VERSION 5.7 ;
BUSBITCHARS "[]" ;
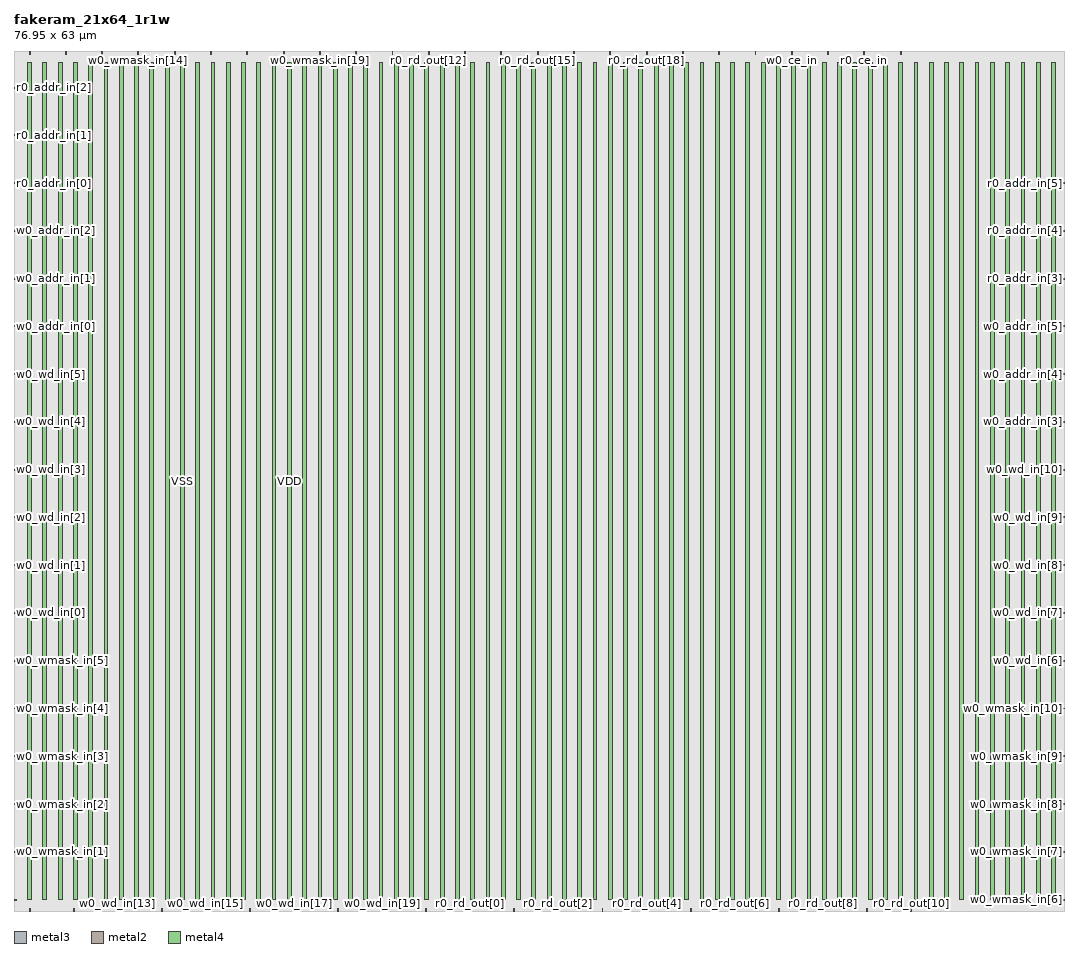
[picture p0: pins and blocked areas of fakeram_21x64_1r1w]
MACRO fakeram_21x64_1r1w
  FOREIGN fakeram_21x64_1r1w 0 0 ;
  SYMMETRY X Y R90 ;
  SIZE 76.950 BY 63.000 ;
  CLASS BLOCK ;
  PIN w0_wmask_in[0]
    DIRECTION INPUT ;
    USE SIGNAL ;
    SHAPE ABUTMENT ;
    PORT
      LAYER metal3 ;
      RECT 0.000 0.805 0.210 0.875 ;
    END
  END w0_wmask_in[0]
  PIN w0_wmask_in[1]
    DIRECTION INPUT ;
    USE SIGNAL ;
    SHAPE ABUTMENT ;
    PORT
      LAYER metal3 ;
      RECT 0.000 4.305 0.210 4.375 ;
    END
  END w0_wmask_in[1]
  PIN w0_wmask_in[2]
    DIRECTION INPUT ;
    USE SIGNAL ;
    SHAPE ABUTMENT ;
    PORT
      LAYER metal3 ;
      RECT 0.000 7.805 0.210 7.875 ;
    END
  END w0_wmask_in[2]
  PIN w0_wmask_in[3]
    DIRECTION INPUT ;
    USE SIGNAL ;
    SHAPE ABUTMENT ;
    PORT
      LAYER metal3 ;
      RECT 0.000 11.305 0.210 11.375 ;
    END
  END w0_wmask_in[3]
  PIN w0_wmask_in[4]
    DIRECTION INPUT ;
    USE SIGNAL ;
    SHAPE ABUTMENT ;
    PORT
      LAYER metal3 ;
      RECT 0.000 14.805 0.210 14.875 ;
    END
  END w0_wmask_in[4]
  PIN w0_wmask_in[5]
    DIRECTION INPUT ;
    USE SIGNAL ;
    SHAPE ABUTMENT ;
    PORT
      LAYER metal3 ;
      RECT 0.000 18.305 0.210 18.375 ;
    END
  END w0_wmask_in[5]
  PIN w0_wmask_in[6]
    DIRECTION INPUT ;
    USE SIGNAL ;
    SHAPE ABUTMENT ;
    PORT
      LAYER metal3 ;
      RECT 76.740 0.805 76.950 0.875 ;
    END
  END w0_wmask_in[6]
  PIN w0_wmask_in[7]
    DIRECTION INPUT ;
    USE SIGNAL ;
    SHAPE ABUTMENT ;
    PORT
      LAYER metal3 ;
      RECT 76.740 4.305 76.950 4.375 ;
    END
  END w0_wmask_in[7]
  PIN w0_wmask_in[8]
    DIRECTION INPUT ;
    USE SIGNAL ;
    SHAPE ABUTMENT ;
    PORT
      LAYER metal3 ;
      RECT 76.740 7.805 76.950 7.875 ;
    END
  END w0_wmask_in[8]
  PIN w0_wmask_in[9]
    DIRECTION INPUT ;
    USE SIGNAL ;
    SHAPE ABUTMENT ;
    PORT
      LAYER metal3 ;
      RECT 76.740 11.305 76.950 11.375 ;
    END
  END w0_wmask_in[9]
  PIN w0_wmask_in[10]
    DIRECTION INPUT ;
    USE SIGNAL ;
    SHAPE ABUTMENT ;
    PORT
      LAYER metal3 ;
      RECT 76.740 14.805 76.950 14.875 ;
    END
  END w0_wmask_in[10]
  PIN w0_wmask_in[11]
    DIRECTION INPUT ;
    USE SIGNAL ;
    SHAPE ABUTMENT ;
    PORT
      LAYER metal2 ;
      RECT 1.105 62.790 1.175 63.000 ;
    END
  END w0_wmask_in[11]
  PIN w0_wmask_in[12]
    DIRECTION INPUT ;
    USE SIGNAL ;
    SHAPE ABUTMENT ;
    PORT
      LAYER metal2 ;
      RECT 3.765 62.790 3.835 63.000 ;
    END
  END w0_wmask_in[12]
  PIN w0_wmask_in[13]
    DIRECTION INPUT ;
    USE SIGNAL ;
    SHAPE ABUTMENT ;
    PORT
      LAYER metal2 ;
      RECT 6.425 62.790 6.495 63.000 ;
    END
  END w0_wmask_in[13]
  PIN w0_wmask_in[14]
    DIRECTION INPUT ;
    USE SIGNAL ;
    SHAPE ABUTMENT ;
    PORT
      LAYER metal2 ;
      RECT 9.085 62.790 9.155 63.000 ;
    END
  END w0_wmask_in[14]
  PIN w0_wmask_in[15]
    DIRECTION INPUT ;
    USE SIGNAL ;
    SHAPE ABUTMENT ;
    PORT
      LAYER metal2 ;
      RECT 11.745 62.790 11.815 63.000 ;
    END
  END w0_wmask_in[15]
  PIN w0_wmask_in[16]
    DIRECTION INPUT ;
    USE SIGNAL ;
    SHAPE ABUTMENT ;
    PORT
      LAYER metal2 ;
      RECT 14.405 62.790 14.475 63.000 ;
    END
  END w0_wmask_in[16]
  PIN w0_wmask_in[17]
    DIRECTION INPUT ;
    USE SIGNAL ;
    SHAPE ABUTMENT ;
    PORT
      LAYER metal2 ;
      RECT 17.065 62.790 17.135 63.000 ;
    END
  END w0_wmask_in[17]
  PIN w0_wmask_in[18]
    DIRECTION INPUT ;
    USE SIGNAL ;
    SHAPE ABUTMENT ;
    PORT
      LAYER metal2 ;
      RECT 19.725 62.790 19.795 63.000 ;
    END
  END w0_wmask_in[18]
  PIN w0_wmask_in[19]
    DIRECTION INPUT ;
    USE SIGNAL ;
    SHAPE ABUTMENT ;
    PORT
      LAYER metal2 ;
      RECT 22.385 62.790 22.455 63.000 ;
    END
  END w0_wmask_in[19]
  PIN w0_wmask_in[20]
    DIRECTION INPUT ;
    USE SIGNAL ;
    SHAPE ABUTMENT ;
    PORT
      LAYER metal2 ;
      RECT 25.045 62.790 25.115 63.000 ;
    END
  END w0_wmask_in[20]
  PIN w0_wd_in[0]
    DIRECTION INPUT ;
    USE SIGNAL ;
    SHAPE ABUTMENT ;
    PORT
      LAYER metal3 ;
      RECT 0.000 21.805 0.210 21.875 ;
    END
  END w0_wd_in[0]
  PIN w0_wd_in[1]
    DIRECTION INPUT ;
    USE SIGNAL ;
    SHAPE ABUTMENT ;
    PORT
      LAYER metal3 ;
      RECT 0.000 25.305 0.210 25.375 ;
    END
  END w0_wd_in[1]
  PIN w0_wd_in[2]
    DIRECTION INPUT ;
    USE SIGNAL ;
    SHAPE ABUTMENT ;
    PORT
      LAYER metal3 ;
      RECT 0.000 28.805 0.210 28.875 ;
    END
  END w0_wd_in[2]
  PIN w0_wd_in[3]
    DIRECTION INPUT ;
    USE SIGNAL ;
    SHAPE ABUTMENT ;
    PORT
      LAYER metal3 ;
      RECT 0.000 32.305 0.210 32.375 ;
    END
  END w0_wd_in[3]
  PIN w0_wd_in[4]
    DIRECTION INPUT ;
    USE SIGNAL ;
    SHAPE ABUTMENT ;
    PORT
      LAYER metal3 ;
      RECT 0.000 35.805 0.210 35.875 ;
    END
  END w0_wd_in[4]
  PIN w0_wd_in[5]
    DIRECTION INPUT ;
    USE SIGNAL ;
    SHAPE ABUTMENT ;
    PORT
      LAYER metal3 ;
      RECT 0.000 39.305 0.210 39.375 ;
    END
  END w0_wd_in[5]
  PIN w0_wd_in[6]
    DIRECTION INPUT ;
    USE SIGNAL ;
    SHAPE ABUTMENT ;
    PORT
      LAYER metal3 ;
      RECT 76.740 18.305 76.950 18.375 ;
    END
  END w0_wd_in[6]
  PIN w0_wd_in[7]
    DIRECTION INPUT ;
    USE SIGNAL ;
    SHAPE ABUTMENT ;
    PORT
      LAYER metal3 ;
      RECT 76.740 21.805 76.950 21.875 ;
    END
  END w0_wd_in[7]
  PIN w0_wd_in[8]
    DIRECTION INPUT ;
    USE SIGNAL ;
    SHAPE ABUTMENT ;
    PORT
      LAYER metal3 ;
      RECT 76.740 25.305 76.950 25.375 ;
    END
  END w0_wd_in[8]
  PIN w0_wd_in[9]
    DIRECTION INPUT ;
    USE SIGNAL ;
    SHAPE ABUTMENT ;
    PORT
      LAYER metal3 ;
      RECT 76.740 28.805 76.950 28.875 ;
    END
  END w0_wd_in[9]
  PIN w0_wd_in[10]
    DIRECTION INPUT ;
    USE SIGNAL ;
    SHAPE ABUTMENT ;
    PORT
      LAYER metal3 ;
      RECT 76.740 32.305 76.950 32.375 ;
    END
  END w0_wd_in[10]
  PIN w0_wd_in[11]
    DIRECTION INPUT ;
    USE SIGNAL ;
    SHAPE ABUTMENT ;
    PORT
      LAYER metal2 ;
      RECT 1.105 0.000 1.175 0.210 ;
    END
  END w0_wd_in[11]
  PIN w0_wd_in[12]
    DIRECTION INPUT ;
    USE SIGNAL ;
    SHAPE ABUTMENT ;
    PORT
      LAYER metal2 ;
      RECT 4.335 0.000 4.405 0.210 ;
    END
  END w0_wd_in[12]
  PIN w0_wd_in[13]
    DIRECTION INPUT ;
    USE SIGNAL ;
    SHAPE ABUTMENT ;
    PORT
      LAYER metal2 ;
      RECT 7.565 0.000 7.635 0.210 ;
    END
  END w0_wd_in[13]
  PIN w0_wd_in[14]
    DIRECTION INPUT ;
    USE SIGNAL ;
    SHAPE ABUTMENT ;
    PORT
      LAYER metal2 ;
      RECT 10.795 0.000 10.865 0.210 ;
    END
  END w0_wd_in[14]
  PIN w0_wd_in[15]
    DIRECTION INPUT ;
    USE SIGNAL ;
    SHAPE ABUTMENT ;
    PORT
      LAYER metal2 ;
      RECT 14.025 0.000 14.095 0.210 ;
    END
  END w0_wd_in[15]
  PIN w0_wd_in[16]
    DIRECTION INPUT ;
    USE SIGNAL ;
    SHAPE ABUTMENT ;
    PORT
      LAYER metal2 ;
      RECT 17.255 0.000 17.325 0.210 ;
    END
  END w0_wd_in[16]
  PIN w0_wd_in[17]
    DIRECTION INPUT ;
    USE SIGNAL ;
    SHAPE ABUTMENT ;
    PORT
      LAYER metal2 ;
      RECT 20.485 0.000 20.555 0.210 ;
    END
  END w0_wd_in[17]
  PIN w0_wd_in[18]
    DIRECTION INPUT ;
    USE SIGNAL ;
    SHAPE ABUTMENT ;
    PORT
      LAYER metal2 ;
      RECT 23.715 0.000 23.785 0.210 ;
    END
  END w0_wd_in[18]
  PIN w0_wd_in[19]
    DIRECTION INPUT ;
    USE SIGNAL ;
    SHAPE ABUTMENT ;
    PORT
      LAYER metal2 ;
      RECT 26.945 0.000 27.015 0.210 ;
    END
  END w0_wd_in[19]
  PIN w0_wd_in[20]
    DIRECTION INPUT ;
    USE SIGNAL ;
    SHAPE ABUTMENT ;
    PORT
      LAYER metal2 ;
      RECT 30.175 0.000 30.245 0.210 ;
    END
  END w0_wd_in[20]
  PIN r0_rd_out[0]
    DIRECTION OUTPUT ;
    USE SIGNAL ;
    SHAPE ABUTMENT ;
    PORT
      LAYER metal2 ;
      RECT 33.405 0.000 33.475 0.210 ;
    END
  END r0_rd_out[0]
  PIN r0_rd_out[1]
    DIRECTION OUTPUT ;
    USE SIGNAL ;
    SHAPE ABUTMENT ;
    PORT
      LAYER metal2 ;
      RECT 36.635 0.000 36.705 0.210 ;
    END
  END r0_rd_out[1]
  PIN r0_rd_out[2]
    DIRECTION OUTPUT ;
    USE SIGNAL ;
    SHAPE ABUTMENT ;
    PORT
      LAYER metal2 ;
      RECT 39.865 0.000 39.935 0.210 ;
    END
  END r0_rd_out[2]
  PIN r0_rd_out[3]
    DIRECTION OUTPUT ;
    USE SIGNAL ;
    SHAPE ABUTMENT ;
    PORT
      LAYER metal2 ;
      RECT 43.095 0.000 43.165 0.210 ;
    END
  END r0_rd_out[3]
  PIN r0_rd_out[4]
    DIRECTION OUTPUT ;
    USE SIGNAL ;
    SHAPE ABUTMENT ;
    PORT
      LAYER metal2 ;
      RECT 46.325 0.000 46.395 0.210 ;
    END
  END r0_rd_out[4]
  PIN r0_rd_out[5]
    DIRECTION OUTPUT ;
    USE SIGNAL ;
    SHAPE ABUTMENT ;
    PORT
      LAYER metal2 ;
      RECT 49.555 0.000 49.625 0.210 ;
    END
  END r0_rd_out[5]
  PIN r0_rd_out[6]
    DIRECTION OUTPUT ;
    USE SIGNAL ;
    SHAPE ABUTMENT ;
    PORT
      LAYER metal2 ;
      RECT 52.785 0.000 52.855 0.210 ;
    END
  END r0_rd_out[6]
  PIN r0_rd_out[7]
    DIRECTION OUTPUT ;
    USE SIGNAL ;
    SHAPE ABUTMENT ;
    PORT
      LAYER metal2 ;
      RECT 56.015 0.000 56.085 0.210 ;
    END
  END r0_rd_out[7]
  PIN r0_rd_out[8]
    DIRECTION OUTPUT ;
    USE SIGNAL ;
    SHAPE ABUTMENT ;
    PORT
      LAYER metal2 ;
      RECT 59.245 0.000 59.315 0.210 ;
    END
  END r0_rd_out[8]
  PIN r0_rd_out[9]
    DIRECTION OUTPUT ;
    USE SIGNAL ;
    SHAPE ABUTMENT ;
    PORT
      LAYER metal2 ;
      RECT 62.475 0.000 62.545 0.210 ;
    END
  END r0_rd_out[9]
  PIN r0_rd_out[10]
    DIRECTION OUTPUT ;
    USE SIGNAL ;
    SHAPE ABUTMENT ;
    PORT
      LAYER metal2 ;
      RECT 65.705 0.000 65.775 0.210 ;
    END
  END r0_rd_out[10]
  PIN r0_rd_out[11]
    DIRECTION OUTPUT ;
    USE SIGNAL ;
    SHAPE ABUTMENT ;
    PORT
      LAYER metal2 ;
      RECT 27.705 62.790 27.775 63.000 ;
    END
  END r0_rd_out[11]
  PIN r0_rd_out[12]
    DIRECTION OUTPUT ;
    USE SIGNAL ;
    SHAPE ABUTMENT ;
    PORT
      LAYER metal2 ;
      RECT 30.365 62.790 30.435 63.000 ;
    END
  END r0_rd_out[12]
  PIN r0_rd_out[13]
    DIRECTION OUTPUT ;
    USE SIGNAL ;
    SHAPE ABUTMENT ;
    PORT
      LAYER metal2 ;
      RECT 33.025 62.790 33.095 63.000 ;
    END
  END r0_rd_out[13]
  PIN r0_rd_out[14]
    DIRECTION OUTPUT ;
    USE SIGNAL ;
    SHAPE ABUTMENT ;
    PORT
      LAYER metal2 ;
      RECT 35.685 62.790 35.755 63.000 ;
    END
  END r0_rd_out[14]
  PIN r0_rd_out[15]
    DIRECTION OUTPUT ;
    USE SIGNAL ;
    SHAPE ABUTMENT ;
    PORT
      LAYER metal2 ;
      RECT 38.345 62.790 38.415 63.000 ;
    END
  END r0_rd_out[15]
  PIN r0_rd_out[16]
    DIRECTION OUTPUT ;
    USE SIGNAL ;
    SHAPE ABUTMENT ;
    PORT
      LAYER metal2 ;
      RECT 41.005 62.790 41.075 63.000 ;
    END
  END r0_rd_out[16]
  PIN r0_rd_out[17]
    DIRECTION OUTPUT ;
    USE SIGNAL ;
    SHAPE ABUTMENT ;
    PORT
      LAYER metal2 ;
      RECT 43.665 62.790 43.735 63.000 ;
    END
  END r0_rd_out[17]
  PIN r0_rd_out[18]
    DIRECTION OUTPUT ;
    USE SIGNAL ;
    SHAPE ABUTMENT ;
    PORT
      LAYER metal2 ;
      RECT 46.325 62.790 46.395 63.000 ;
    END
  END r0_rd_out[18]
  PIN r0_rd_out[19]
    DIRECTION OUTPUT ;
    USE SIGNAL ;
    SHAPE ABUTMENT ;
    PORT
      LAYER metal2 ;
      RECT 48.985 62.790 49.055 63.000 ;
    END
  END r0_rd_out[19]
  PIN r0_rd_out[20]
    DIRECTION OUTPUT ;
    USE SIGNAL ;
    SHAPE ABUTMENT ;
    PORT
      LAYER metal2 ;
      RECT 51.645 62.790 51.715 63.000 ;
    END
  END r0_rd_out[20]
  PIN w0_addr_in[0]
    DIRECTION INPUT ;
    USE SIGNAL ;
    SHAPE ABUTMENT ;
    PORT
      LAYER metal3 ;
      RECT 0.000 42.805 0.210 42.875 ;
    END
  END w0_addr_in[0]
  PIN w0_addr_in[1]
    DIRECTION INPUT ;
    USE SIGNAL ;
    SHAPE ABUTMENT ;
    PORT
      LAYER metal3 ;
      RECT 0.000 46.305 0.210 46.375 ;
    END
  END w0_addr_in[1]
  PIN w0_addr_in[2]
    DIRECTION INPUT ;
    USE SIGNAL ;
    SHAPE ABUTMENT ;
    PORT
      LAYER metal3 ;
      RECT 0.000 49.805 0.210 49.875 ;
    END
  END w0_addr_in[2]
  PIN w0_addr_in[3]
    DIRECTION INPUT ;
    USE SIGNAL ;
    SHAPE ABUTMENT ;
    PORT
      LAYER metal3 ;
      RECT 76.740 35.805 76.950 35.875 ;
    END
  END w0_addr_in[3]
  PIN w0_addr_in[4]
    DIRECTION INPUT ;
    USE SIGNAL ;
    SHAPE ABUTMENT ;
    PORT
      LAYER metal3 ;
      RECT 76.740 39.305 76.950 39.375 ;
    END
  END w0_addr_in[4]
  PIN w0_addr_in[5]
    DIRECTION INPUT ;
    USE SIGNAL ;
    SHAPE ABUTMENT ;
    PORT
      LAYER metal3 ;
      RECT 76.740 42.805 76.950 42.875 ;
    END
  END w0_addr_in[5]
  PIN r0_addr_in[0]
    DIRECTION INPUT ;
    USE SIGNAL ;
    SHAPE ABUTMENT ;
    PORT
      LAYER metal3 ;
      RECT 0.000 53.305 0.210 53.375 ;
    END
  END r0_addr_in[0]
  PIN r0_addr_in[1]
    DIRECTION INPUT ;
    USE SIGNAL ;
    SHAPE ABUTMENT ;
    PORT
      LAYER metal3 ;
      RECT 0.000 56.805 0.210 56.875 ;
    END
  END r0_addr_in[1]
  PIN r0_addr_in[2]
    DIRECTION INPUT ;
    USE SIGNAL ;
    SHAPE ABUTMENT ;
    PORT
      LAYER metal3 ;
      RECT 0.000 60.305 0.210 60.375 ;
    END
  END r0_addr_in[2]
  PIN r0_addr_in[3]
    DIRECTION INPUT ;
    USE SIGNAL ;
    SHAPE ABUTMENT ;
    PORT
      LAYER metal3 ;
      RECT 76.740 46.305 76.950 46.375 ;
    END
  END r0_addr_in[3]
  PIN r0_addr_in[4]
    DIRECTION INPUT ;
    USE SIGNAL ;
    SHAPE ABUTMENT ;
    PORT
      LAYER metal3 ;
      RECT 76.740 49.805 76.950 49.875 ;
    END
  END r0_addr_in[4]
  PIN r0_addr_in[5]
    DIRECTION INPUT ;
    USE SIGNAL ;
    SHAPE ABUTMENT ;
    PORT
      LAYER metal3 ;
      RECT 76.740 53.305 76.950 53.375 ;
    END
  END r0_addr_in[5]
  PIN w0_we_in
    DIRECTION INPUT ;
    USE SIGNAL ;
    SHAPE ABUTMENT ;
    PORT
      LAYER metal2 ;
      RECT 54.305 62.790 54.375 63.000 ;
    END
  END w0_we_in
  PIN w0_ce_in
    DIRECTION INPUT ;
    USE SIGNAL ;
    SHAPE ABUTMENT ;
    PORT
      LAYER metal2 ;
      RECT 56.965 62.790 57.035 63.000 ;
    END
  END w0_ce_in
  PIN w0_clk
    DIRECTION INPUT ;
    USE SIGNAL ;
    SHAPE ABUTMENT ;
    PORT
      LAYER metal2 ;
      RECT 59.625 62.790 59.695 63.000 ;
    END
  END w0_clk
  PIN r0_ce_in
    DIRECTION INPUT ;
    USE SIGNAL ;
    SHAPE ABUTMENT ;
    PORT
      LAYER metal2 ;
      RECT 62.285 62.790 62.355 63.000 ;
    END
  END r0_ce_in
  PIN r0_clk
    DIRECTION INPUT ;
    USE SIGNAL ;
    SHAPE ABUTMENT ;
    PORT
      LAYER metal2 ;
      RECT 64.945 62.790 65.015 63.000 ;
    END
  END r0_clk
  PIN VSS
    DIRECTION INOUT ;
    USE GROUND ;
    PORT
      LAYER metal4 ;
      RECT 1.000 0.840 1.280 62.160 ;
      RECT 3.240 0.840 3.520 62.160 ;
      RECT 5.480 0.840 5.760 62.160 ;
      RECT 7.720 0.840 8.000 62.160 ;
      RECT 9.960 0.840 10.240 62.160 ;
      RECT 12.200 0.840 12.480 62.160 ;
      RECT 14.440 0.840 14.720 62.160 ;
      RECT 16.680 0.840 16.960 62.160 ;
      RECT 18.920 0.840 19.200 62.160 ;
      RECT 21.160 0.840 21.440 62.160 ;
      RECT 23.400 0.840 23.680 62.160 ;
      RECT 25.640 0.840 25.920 62.160 ;
      RECT 27.880 0.840 28.160 62.160 ;
      RECT 30.120 0.840 30.400 62.160 ;
      RECT 32.360 0.840 32.640 62.160 ;
      RECT 34.600 0.840 34.880 62.160 ;
      RECT 36.840 0.840 37.120 62.160 ;
      RECT 39.080 0.840 39.360 62.160 ;
      RECT 41.320 0.840 41.600 62.160 ;
      RECT 43.560 0.840 43.840 62.160 ;
      RECT 45.800 0.840 46.080 62.160 ;
      RECT 48.040 0.840 48.320 62.160 ;
      RECT 50.280 0.840 50.560 62.160 ;
      RECT 52.520 0.840 52.800 62.160 ;
      RECT 54.760 0.840 55.040 62.160 ;
      RECT 57.000 0.840 57.280 62.160 ;
      RECT 59.240 0.840 59.520 62.160 ;
      RECT 61.480 0.840 61.760 62.160 ;
      RECT 63.720 0.840 64.000 62.160 ;
      RECT 65.960 0.840 66.240 62.160 ;
      RECT 68.200 0.840 68.480 62.160 ;
      RECT 70.440 0.840 70.720 62.160 ;
      RECT 72.680 0.840 72.960 62.160 ;
      RECT 74.920 0.840 75.200 62.160 ;
    END
  END VSS
  PIN VDD
    DIRECTION INOUT ;
    USE POWER ;
    PORT
      LAYER metal4 ;
      RECT 2.120 0.840 2.400 62.160 ;
      RECT 4.360 0.840 4.640 62.160 ;
      RECT 6.600 0.840 6.880 62.160 ;
      RECT 8.840 0.840 9.120 62.160 ;
      RECT 11.080 0.840 11.360 62.160 ;
      RECT 13.320 0.840 13.600 62.160 ;
      RECT 15.560 0.840 15.840 62.160 ;
      RECT 17.800 0.840 18.080 62.160 ;
      RECT 20.040 0.840 20.320 62.160 ;
      RECT 22.280 0.840 22.560 62.160 ;
      RECT 24.520 0.840 24.800 62.160 ;
      RECT 26.760 0.840 27.040 62.160 ;
      RECT 29.000 0.840 29.280 62.160 ;
      RECT 31.240 0.840 31.520 62.160 ;
      RECT 33.480 0.840 33.760 62.160 ;
      RECT 35.720 0.840 36.000 62.160 ;
      RECT 37.960 0.840 38.240 62.160 ;
      RECT 40.200 0.840 40.480 62.160 ;
      RECT 42.440 0.840 42.720 62.160 ;
      RECT 44.680 0.840 44.960 62.160 ;
      RECT 46.920 0.840 47.200 62.160 ;
      RECT 49.160 0.840 49.440 62.160 ;
      RECT 51.400 0.840 51.680 62.160 ;
      RECT 53.640 0.840 53.920 62.160 ;
      RECT 55.880 0.840 56.160 62.160 ;
      RECT 58.120 0.840 58.400 62.160 ;
      RECT 60.360 0.840 60.640 62.160 ;
      RECT 62.600 0.840 62.880 62.160 ;
      RECT 64.840 0.840 65.120 62.160 ;
      RECT 67.080 0.840 67.360 62.160 ;
      RECT 69.320 0.840 69.600 62.160 ;
      RECT 71.560 0.840 71.840 62.160 ;
      RECT 73.800 0.840 74.080 62.160 ;
      RECT 76.040 0.840 76.320 62.160 ;
    END
  END VDD
  OBS
    LAYER metal1 ;
    RECT 0 0 76.950 63.000 ;
    LAYER metal2 ;
    RECT 0 0 76.950 63.000 ;
    LAYER metal3 ;
    RECT 0 0 76.950 63.000 ;
    LAYER metal4 ;
    RECT 0 0 76.950 63.000 ;
    LAYER OVERLAP ;
    RECT 0 0 76.950 63.000 ;
  END
END fakeram_21x64_1r1w

END LIBRARY
